VERSION 5.7 ;
  NOWIREEXTENSIONATPIN ON ;
  DIVIDERCHAR "/" ;
  BUSBITCHARS "[]" ;
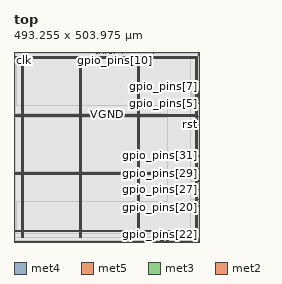
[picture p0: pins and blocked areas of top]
MACRO top
  CLASS BLOCK ;
  FOREIGN top ;
  ORIGIN 0.000 0.000 ;
  SIZE 493.255 BY 503.975 ;
  PIN VGND
    DIRECTION INOUT ;
    USE GROUND ;
    PORT
      LAYER met4 ;
        RECT 24.340 10.640 25.940 492.560 ;
    END
    PORT
      LAYER met4 ;
        RECT 177.940 10.640 179.540 492.560 ;
    END
    PORT
      LAYER met4 ;
        RECT 331.540 10.640 333.140 492.560 ;
    END
    PORT
      LAYER met4 ;
        RECT 485.140 10.640 486.740 492.560 ;
    END
    PORT
      LAYER met5 ;
        RECT 5.280 30.030 487.840 31.630 ;
    END
    PORT
      LAYER met5 ;
        RECT 5.280 183.210 487.840 184.810 ;
    END
    PORT
      LAYER met5 ;
        RECT 5.280 336.390 487.840 337.990 ;
    END
    PORT
      LAYER met5 ;
        RECT 5.280 489.570 487.840 491.170 ;
    END
  END VGND
  PIN VPWR
    DIRECTION INOUT ;
    USE POWER ;
    PORT
      LAYER met4 ;
        RECT 21.040 10.640 22.640 492.560 ;
    END
    PORT
      LAYER met4 ;
        RECT 174.640 10.640 176.240 492.560 ;
    END
    PORT
      LAYER met4 ;
        RECT 328.240 10.640 329.840 492.560 ;
    END
    PORT
      LAYER met4 ;
        RECT 481.840 10.640 483.440 492.560 ;
    END
    PORT
      LAYER met5 ;
        RECT 5.280 26.730 487.840 28.330 ;
    END
    PORT
      LAYER met5 ;
        RECT 5.280 179.910 487.840 181.510 ;
    END
    PORT
      LAYER met5 ;
        RECT 5.280 333.090 487.840 334.690 ;
    END
    PORT
      LAYER met5 ;
        RECT 5.280 486.270 487.840 487.870 ;
    END
  END VPWR
  PIN clk
    DIRECTION INPUT ;
    USE SIGNAL ;
    ANTENNAGATEAREA 0.852000 ;
    PORT
      LAYER met3 ;
        RECT 0.000 486.240 4.000 486.840 ;
    END
  END clk
  PIN gpio_pins[0]
    DIRECTION INOUT ;
    USE SIGNAL ;
    ANTENNAGATEAREA 0.252000 ;
    ANTENNADIFFAREA 0.891000 ;
    PORT
      LAYER met3 ;
        RECT 489.255 394.440 493.255 395.040 ;
    END
  END gpio_pins[0]
  PIN gpio_pins[10]
    DIRECTION INOUT ;
    USE SIGNAL ;
    ANTENNAGATEAREA 0.252000 ;
    ANTENNADIFFAREA 0.445500 ;
    PORT
      LAYER met2 ;
        RECT 267.350 499.975 267.630 503.975 ;
    END
  END gpio_pins[10]
  PIN gpio_pins[11]
    DIRECTION INOUT ;
    USE SIGNAL ;
    ANTENNAGATEAREA 0.252000 ;
    ANTENNADIFFAREA 0.445500 ;
    PORT
      LAYER met2 ;
        RECT 286.670 499.975 286.950 503.975 ;
    END
  END gpio_pins[11]
  PIN gpio_pins[12]
    DIRECTION INOUT ;
    USE SIGNAL ;
    ANTENNAGATEAREA 0.252000 ;
    ANTENNADIFFAREA 0.891000 ;
    PORT
      LAYER met2 ;
        RECT 257.690 499.975 257.970 503.975 ;
    END
  END gpio_pins[12]
  PIN gpio_pins[13]
    DIRECTION INOUT ;
    USE SIGNAL ;
    ANTENNAGATEAREA 0.252000 ;
    ANTENNADIFFAREA 0.445500 ;
    PORT
      LAYER met2 ;
        RECT 254.470 499.975 254.750 503.975 ;
    END
  END gpio_pins[13]
  PIN gpio_pins[14]
    DIRECTION INOUT ;
    USE SIGNAL ;
    ANTENNAGATEAREA 0.252000 ;
    ANTENNADIFFAREA 0.891000 ;
    PORT
      LAYER met2 ;
        RECT 222.270 499.975 222.550 503.975 ;
    END
  END gpio_pins[14]
  PIN gpio_pins[15]
    DIRECTION INOUT ;
    USE SIGNAL ;
    ANTENNAGATEAREA 0.252000 ;
    ANTENNADIFFAREA 0.891000 ;
    PORT
      LAYER met2 ;
        RECT 225.490 499.975 225.770 503.975 ;
    END
  END gpio_pins[15]
  PIN gpio_pins[16]
    DIRECTION INOUT ;
    USE SIGNAL ;
    ANTENNAGATEAREA 0.252000 ;
    ANTENNADIFFAREA 0.891000 ;
    PORT
      LAYER met2 ;
        RECT 241.590 499.975 241.870 503.975 ;
    END
  END gpio_pins[16]
  PIN gpio_pins[17]
    DIRECTION INOUT ;
    USE SIGNAL ;
    ANTENNAGATEAREA 0.252000 ;
    ANTENNADIFFAREA 0.891000 ;
    PORT
      LAYER met2 ;
        RECT 219.050 499.975 219.330 503.975 ;
    END
  END gpio_pins[17]
  PIN gpio_pins[18]
    DIRECTION INOUT ;
    USE SIGNAL ;
    ANTENNAGATEAREA 0.252000 ;
    ANTENNADIFFAREA 0.891000 ;
    PORT
      LAYER met2 ;
        RECT 238.370 499.975 238.650 503.975 ;
    END
  END gpio_pins[18]
  PIN gpio_pins[19]
    DIRECTION INOUT ;
    USE SIGNAL ;
    ANTENNAGATEAREA 0.252000 ;
    ANTENNADIFFAREA 0.445500 ;
    PORT
      LAYER met2 ;
        RECT 370.390 499.975 370.670 503.975 ;
    END
  END gpio_pins[19]
  PIN gpio_pins[1]
    DIRECTION INOUT ;
    USE SIGNAL ;
    ANTENNAGATEAREA 0.252000 ;
    ANTENNADIFFAREA 0.891000 ;
    PORT
      LAYER met3 ;
        RECT 489.255 387.640 493.255 388.240 ;
    END
  END gpio_pins[1]
  PIN gpio_pins[20]
    DIRECTION INOUT ;
    USE SIGNAL ;
    ANTENNAGATEAREA 0.252000 ;
    ANTENNADIFFAREA 0.891000 ;
    PORT
      LAYER met3 ;
        RECT 489.255 112.240 493.255 112.840 ;
    END
  END gpio_pins[20]
  PIN gpio_pins[21]
    DIRECTION INOUT ;
    USE SIGNAL ;
    ANTENNAGATEAREA 0.252000 ;
    ANTENNADIFFAREA 0.891000 ;
    PORT
      LAYER met2 ;
        RECT 396.150 0.000 396.430 4.000 ;
    END
  END gpio_pins[21]
  PIN gpio_pins[22]
    DIRECTION INOUT ;
    USE SIGNAL ;
    ANTENNAGATEAREA 0.252000 ;
    ANTENNADIFFAREA 0.891000 ;
    PORT
      LAYER met2 ;
        RECT 405.810 0.000 406.090 4.000 ;
    END
  END gpio_pins[22]
  PIN gpio_pins[23]
    DIRECTION INOUT ;
    USE SIGNAL ;
    ANTENNAGATEAREA 0.252000 ;
    ANTENNADIFFAREA 0.891000 ;
    PORT
      LAYER met2 ;
        RECT 389.710 0.000 389.990 4.000 ;
    END
  END gpio_pins[23]
  PIN gpio_pins[24]
    DIRECTION INOUT ;
    USE SIGNAL ;
    ANTENNAGATEAREA 0.252000 ;
    ANTENNADIFFAREA 0.891000 ;
    PORT
      LAYER met2 ;
        RECT 409.030 0.000 409.310 4.000 ;
    END
  END gpio_pins[24]
  PIN gpio_pins[25]
    DIRECTION INOUT ;
    USE SIGNAL ;
    ANTENNAGATEAREA 0.252000 ;
    ANTENNADIFFAREA 0.891000 ;
    PORT
      LAYER met2 ;
        RECT 392.930 0.000 393.210 4.000 ;
    END
  END gpio_pins[25]
  PIN gpio_pins[26]
    DIRECTION INOUT ;
    USE SIGNAL ;
    ANTENNAGATEAREA 0.252000 ;
    ANTENNADIFFAREA 0.891000 ;
    PORT
      LAYER met3 ;
        RECT 489.255 105.440 493.255 106.040 ;
    END
  END gpio_pins[26]
  PIN gpio_pins[27]
    DIRECTION INOUT ;
    USE SIGNAL ;
    ANTENNAGATEAREA 0.252000 ;
    ANTENNADIFFAREA 0.891000 ;
    PORT
      LAYER met3 ;
        RECT 489.255 139.440 493.255 140.040 ;
    END
  END gpio_pins[27]
  PIN gpio_pins[28]
    DIRECTION INOUT ;
    USE SIGNAL ;
    ANTENNAGATEAREA 0.252000 ;
    ANTENNADIFFAREA 0.891000 ;
    PORT
      LAYER met3 ;
        RECT 489.255 95.240 493.255 95.840 ;
    END
  END gpio_pins[28]
  PIN gpio_pins[29]
    DIRECTION INOUT ;
    USE SIGNAL ;
    ANTENNAGATEAREA 0.252000 ;
    ANTENNADIFFAREA 0.891000 ;
    PORT
      LAYER met3 ;
        RECT 489.255 159.840 493.255 160.440 ;
    END
  END gpio_pins[29]
  PIN gpio_pins[2]
    DIRECTION INOUT ;
    USE SIGNAL ;
    ANTENNAGATEAREA 0.252000 ;
    ANTENNADIFFAREA 0.891000 ;
    PORT
      LAYER met3 ;
        RECT 489.255 380.840 493.255 381.440 ;
    END
  END gpio_pins[2]
  PIN gpio_pins[30]
    DIRECTION INOUT ;
    USE SIGNAL ;
    ANTENNAGATEAREA 0.252000 ;
    ANTENNADIFFAREA 0.891000 ;
    PORT
      LAYER met3 ;
        RECT 489.255 193.840 493.255 194.440 ;
    END
  END gpio_pins[30]
  PIN gpio_pins[31]
    DIRECTION INOUT ;
    USE SIGNAL ;
    ANTENNAGATEAREA 0.252000 ;
    ANTENNADIFFAREA 0.891000 ;
    PORT
      LAYER met3 ;
        RECT 489.255 227.840 493.255 228.440 ;
    END
  END gpio_pins[31]
  PIN gpio_pins[3]
    DIRECTION INOUT ;
    USE SIGNAL ;
    ANTENNAGATEAREA 0.252000 ;
    ANTENNADIFFAREA 0.891000 ;
    PORT
      LAYER met3 ;
        RECT 489.255 370.640 493.255 371.240 ;
    END
  END gpio_pins[3]
  PIN gpio_pins[4]
    DIRECTION INOUT ;
    USE SIGNAL ;
    ANTENNAGATEAREA 0.252000 ;
    ANTENNADIFFAREA 0.891000 ;
    PORT
      LAYER met3 ;
        RECT 489.255 397.840 493.255 398.440 ;
    END
  END gpio_pins[4]
  PIN gpio_pins[5]
    DIRECTION INOUT ;
    USE SIGNAL ;
    ANTENNAGATEAREA 0.252000 ;
    ANTENNADIFFAREA 0.891000 ;
    PORT
      LAYER met3 ;
        RECT 489.255 367.240 493.255 367.840 ;
    END
  END gpio_pins[5]
  PIN gpio_pins[6]
    DIRECTION INOUT ;
    USE SIGNAL ;
    ANTENNAGATEAREA 0.252000 ;
    ANTENNADIFFAREA 0.891000 ;
    PORT
      LAYER met3 ;
        RECT 489.255 377.440 493.255 378.040 ;
    END
  END gpio_pins[6]
  PIN gpio_pins[7]
    DIRECTION INOUT ;
    USE SIGNAL ;
    ANTENNAGATEAREA 0.252000 ;
    ANTENNADIFFAREA 0.891000 ;
    PORT
      LAYER met3 ;
        RECT 489.255 391.040 493.255 391.640 ;
    END
  END gpio_pins[7]
  PIN gpio_pins[8]
    DIRECTION INOUT ;
    USE SIGNAL ;
    ANTENNAGATEAREA 0.252000 ;
    ANTENNADIFFAREA 0.891000 ;
    PORT
      LAYER met3 ;
        RECT 489.255 374.040 493.255 374.640 ;
    END
  END gpio_pins[8]
  PIN gpio_pins[9]
    DIRECTION INOUT ;
    USE SIGNAL ;
    ANTENNAGATEAREA 0.252000 ;
    ANTENNADIFFAREA 0.891000 ;
    PORT
      LAYER met3 ;
        RECT 489.255 384.240 493.255 384.840 ;
    END
  END gpio_pins[9]
  PIN of
    DIRECTION OUTPUT ;
    USE SIGNAL ;
    ANTENNADIFFAREA 0.445500 ;
    PORT
      LAYER met3 ;
        RECT 489.255 163.240 493.255 163.840 ;
    END
  END of
  PIN rst
    DIRECTION INPUT ;
    USE SIGNAL ;
    ANTENNAGATEAREA 0.213000 ;
    PORT
      LAYER met3 ;
        RECT 489.255 333.240 493.255 333.840 ;
    END
  END rst
  OBS
      LAYER nwell ;
        RECT 5.330 10.795 487.790 492.510 ;
      LAYER li1 ;
        RECT 5.520 10.795 487.600 492.405 ;
      LAYER met1 ;
        RECT 4.670 10.640 487.900 492.560 ;
      LAYER met2 ;
        RECT 4.700 499.695 218.770 500.210 ;
        RECT 219.610 499.695 221.990 500.210 ;
        RECT 222.830 499.695 225.210 500.210 ;
        RECT 226.050 499.695 238.090 500.210 ;
        RECT 238.930 499.695 241.310 500.210 ;
        RECT 242.150 499.695 254.190 500.210 ;
        RECT 255.030 499.695 257.410 500.210 ;
        RECT 258.250 499.695 267.070 500.210 ;
        RECT 267.910 499.695 286.390 500.210 ;
        RECT 287.230 499.695 370.110 500.210 ;
        RECT 370.950 499.695 487.510 500.210 ;
        RECT 4.700 4.280 487.510 499.695 ;
        RECT 4.700 3.670 389.430 4.280 ;
        RECT 390.270 3.670 392.650 4.280 ;
        RECT 393.490 3.670 395.870 4.280 ;
        RECT 396.710 3.670 405.530 4.280 ;
        RECT 406.370 3.670 408.750 4.280 ;
        RECT 409.590 3.670 487.510 4.280 ;
      LAYER met3 ;
        RECT 4.000 487.240 489.255 492.485 ;
        RECT 4.400 485.840 489.255 487.240 ;
        RECT 4.000 398.840 489.255 485.840 ;
        RECT 4.000 397.440 488.855 398.840 ;
        RECT 4.000 395.440 489.255 397.440 ;
        RECT 4.000 394.040 488.855 395.440 ;
        RECT 4.000 392.040 489.255 394.040 ;
        RECT 4.000 390.640 488.855 392.040 ;
        RECT 4.000 388.640 489.255 390.640 ;
        RECT 4.000 387.240 488.855 388.640 ;
        RECT 4.000 385.240 489.255 387.240 ;
        RECT 4.000 383.840 488.855 385.240 ;
        RECT 4.000 381.840 489.255 383.840 ;
        RECT 4.000 380.440 488.855 381.840 ;
        RECT 4.000 378.440 489.255 380.440 ;
        RECT 4.000 377.040 488.855 378.440 ;
        RECT 4.000 375.040 489.255 377.040 ;
        RECT 4.000 373.640 488.855 375.040 ;
        RECT 4.000 371.640 489.255 373.640 ;
        RECT 4.000 370.240 488.855 371.640 ;
        RECT 4.000 368.240 489.255 370.240 ;
        RECT 4.000 366.840 488.855 368.240 ;
        RECT 4.000 334.240 489.255 366.840 ;
        RECT 4.000 332.840 488.855 334.240 ;
        RECT 4.000 228.840 489.255 332.840 ;
        RECT 4.000 227.440 488.855 228.840 ;
        RECT 4.000 194.840 489.255 227.440 ;
        RECT 4.000 193.440 488.855 194.840 ;
        RECT 4.000 164.240 489.255 193.440 ;
        RECT 4.000 162.840 488.855 164.240 ;
        RECT 4.000 160.840 489.255 162.840 ;
        RECT 4.000 159.440 488.855 160.840 ;
        RECT 4.000 140.440 489.255 159.440 ;
        RECT 4.000 139.040 488.855 140.440 ;
        RECT 4.000 113.240 489.255 139.040 ;
        RECT 4.000 111.840 488.855 113.240 ;
        RECT 4.000 106.440 489.255 111.840 ;
        RECT 4.000 105.040 488.855 106.440 ;
        RECT 4.000 96.240 489.255 105.040 ;
        RECT 4.000 94.840 488.855 96.240 ;
        RECT 4.000 10.715 489.255 94.840 ;
      LAYER met4 ;
        RECT 5.390 23.295 20.640 488.065 ;
        RECT 23.040 23.295 23.940 488.065 ;
        RECT 26.340 23.295 174.240 488.065 ;
        RECT 176.640 23.295 177.540 488.065 ;
        RECT 179.940 23.295 327.840 488.065 ;
        RECT 330.240 23.295 331.140 488.065 ;
        RECT 333.540 23.295 467.065 488.065 ;
      LAYER met5 ;
        RECT 5.180 339.590 406.060 362.900 ;
        RECT 5.180 186.410 406.060 331.490 ;
        RECT 5.180 106.300 406.060 178.310 ;
  END
END top
END LIBRARY

